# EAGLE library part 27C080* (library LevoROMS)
27C080 High Performance CMOS EPROM

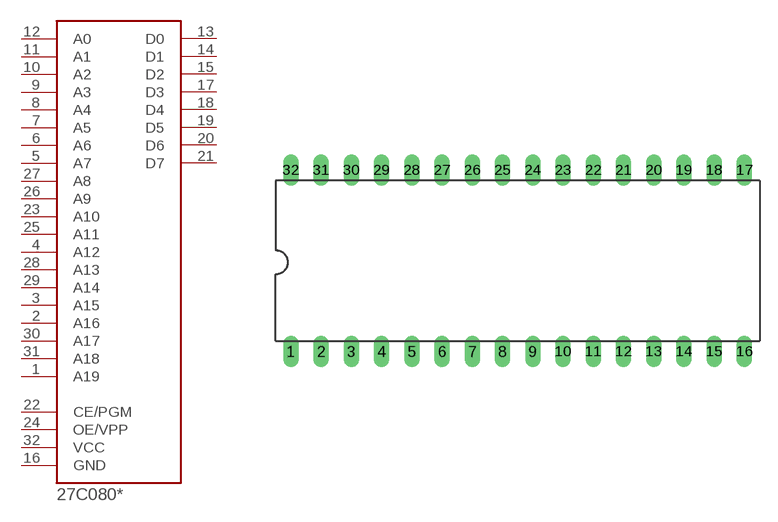
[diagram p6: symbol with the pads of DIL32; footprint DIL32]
Designator prefix IC

## 27C080  [DIL32]
1  A19  in
2  A16  in
3  A15  in
4  A12  in
5  A7  in
6  A6  in
7  A5  in
8  A4  in
9  A3  in
10  A2  in
11  A1  in
12  A0  in
13  D0
14  D1
15  D2
16  GND  pwr
17  D3
18  D4
19  D5
20  D6
21  D7
22  CE/PGM
23  A10  in
24  OE/VPP
25  A11  in
26  A9  in
27  A8  in
28  A13  in
29  A14  in
30  A17  in
31  A18  in
32  VCC  pwr

## Footprint DIL32 (pad centres in mm)
Dual In Line Package
drill 0.813 long: 1 -24.13,-7.62; 2 -21.59,-7.62; 3 -19.05,-7.62; 4 -16.51,-7.62; 5 -13.97,-7.62; 6 -11.43,-7.62; 7 -8.89,-7.62; 8 -6.35,-7.62; 9 -3.81,-7.62; 10 -1.27,-7.62; 11 1.27,-7.62; 12 3.81,-7.62; 13 6.35,-7.62; 14 8.89,-7.62; 15 11.43,-7.62; 16 13.97,-7.62; 17 13.97,7.62; 18 11.43,7.62; 19 8.89,7.62; 20 6.35,7.62; 21 3.81,7.62; 22 1.27,7.62; 23 -1.27,7.62; 24 -3.81,7.62; 25 -6.35,7.62; 26 -8.89,7.62; 27 -11.43,7.62; 28 -13.97,7.62; 29 -16.51,7.62; 30 -19.05,7.62; 31 -21.59,7.62; 32 -24.13,7.62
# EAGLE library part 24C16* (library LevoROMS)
16K (2048 x 8) 2-wire Serial EEPROM

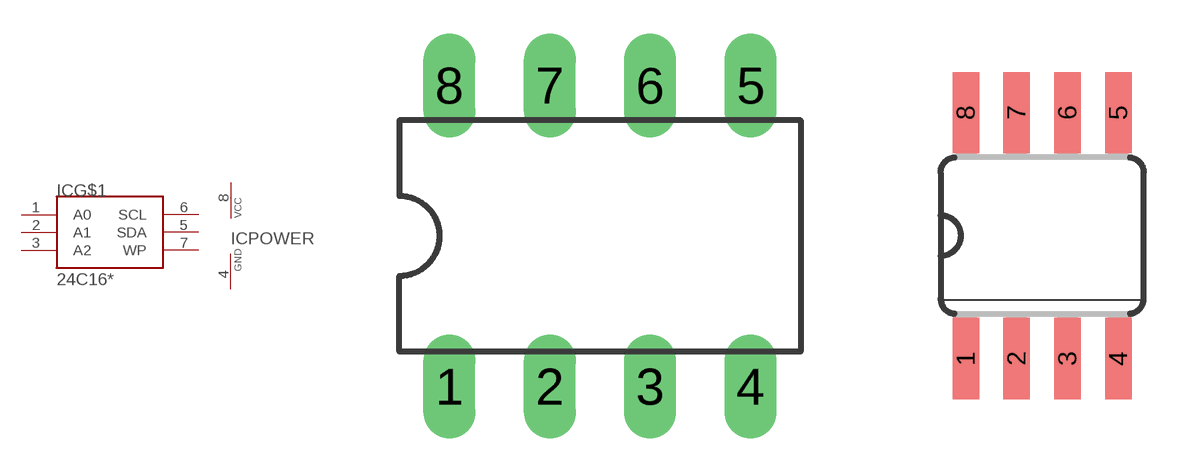
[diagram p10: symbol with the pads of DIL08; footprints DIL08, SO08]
Designator prefix IC; gates G$1=24C02 POWER=VCC-GND

## 24C16DIL  [DIL08]
1  G$1:A0  in
2  G$1:A1  in
3  G$1:A2  in
4  POWER:GND  pwr
5  G$1:SDA
6  G$1:SCL
7  G$1:WP
8  POWER:VCC  pwr

## 24C16SOIC  [SO08]
Pads as for DIL08

## Footprint DIL08 (pad centres in mm)
Dual In Line Package
drill 0.813 long: 1 -3.81,-3.81; 2 -1.27,-3.81; 3 1.27,-3.81; 4 3.81,-3.81; 5 3.81,3.81; 6 1.27,3.81; 7 -1.27,3.81; 8 -3.81,3.81

## Footprint SO08 (pad centres in mm)
Small Outline package 150 mil
smd 0.66 x 2.032: 1 -1.905,-3.073; 2 -0.635,-3.073; 3 0.635,-3.073; 4 1.905,-3.073; 5 1.905,3.073; 6 0.635,3.073; 7 -0.635,3.073; 8 -1.905,3.073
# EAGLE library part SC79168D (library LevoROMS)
Motorola SC79168D Labai slapta mikroschema Printerio HP 400 serijos desifratorius su raktais

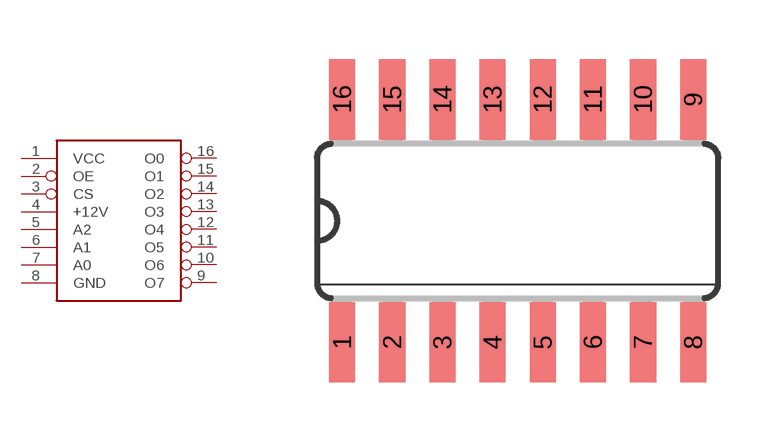
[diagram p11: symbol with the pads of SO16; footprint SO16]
Designator prefix IC

## SC79168D  [SO16]
1  VCC  pwr
2  OE  in
3  CS  in
4  +12V  pwr
5  A2  in
6  A1  in
7  A0  in
8  GND  pwr
9  O7  hiz
10  O6  hiz
11  O5  hiz
12  O4  hiz
13  O3  hiz
14  O2  hiz
15  O1  hiz
16  O0  hiz

## Footprint SO16 (pad centres in mm)
Small Outline package 150 mil
smd 0.66 x 2.032: 1 -4.445,-3.073; 2 -3.175,-3.073; 3 -1.905,-3.073; 4 -0.635,-3.073; 5 0.635,-3.073; 6 1.905,-3.073; 7 3.175,-3.073; 8 4.445,-3.073; 9 4.445,3.073; 10 3.175,3.073; 11 1.905,3.073; 12 0.635,3.073; 13 -0.635,3.073; 14 -1.905,3.073; 15 -3.175,3.073; 16 -4.445,3.073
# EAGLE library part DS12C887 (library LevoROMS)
DS12C887 Real Time Clock RTC

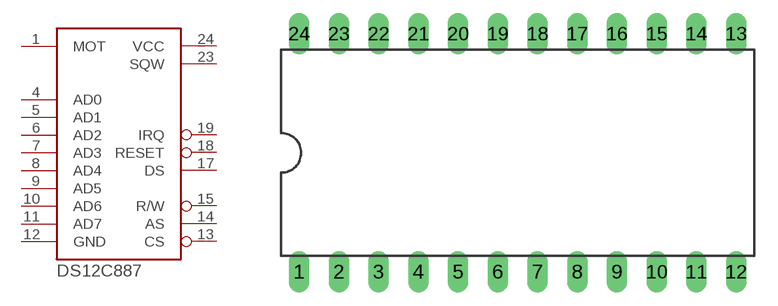
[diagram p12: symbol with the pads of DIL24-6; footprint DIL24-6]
Designator prefix IC

## DS12C887  [DIL24-6]
1  MOT
4  AD0
5  AD1
6  AD2
7  AD3
8  AD4
9  AD5
10  AD6
11  AD7
12  GND  pwr
13  CS
14  AS
15  R/W
17  DS  in
18  RESET
19  IRQ
23  SQW  out
24  VCC  pwr

## Footprint DIL24-6 (pad centres in mm)
Dual In Line Package 0.6 inch
drill 0.813 long: 1 -13.97,-7.62; 2 -11.43,-7.62; 3 -8.89,-7.62; 4 -6.35,-7.62; 5 -3.81,-7.62; 6 -1.27,-7.62; 7 1.27,-7.62; 8 3.81,-7.62; 9 6.35,-7.62; 10 8.89,-7.62; 11 11.43,-7.62; 12 13.97,-7.62; 13 13.97,7.62; 14 11.43,7.62; 15 8.89,7.62; 16 6.35,7.62; 17 3.81,7.62; 18 1.27,7.62; 19 -1.27,7.62; 20 -3.81,7.62; 21 -6.35,7.62; 22 -8.89,7.62; 23 -11.43,7.62; 24 -13.97,7.62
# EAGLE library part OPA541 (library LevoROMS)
OPA541 High Power Monolithic OPERATIONAL AMPLIFIER The OPA541 is a power operational amplifier capable of operation from power supplies up to ±40V and delivering continuous output currents up to 5A. Internal current limit circuitry can be user-programmed with a single external resistor, protecting the amplifier and load from fault conditions The OPA541 is available in an 11-pin power plastic package and an industry-standard 8-pin TO-3 hermetic package. The power plastic package has a copper- lead frame to maximize heat transfer. The TO-3 package is isolated from all circuitry, allowing it to be mounted directly to a heat sink without special insulators. BurrBrown/TI product

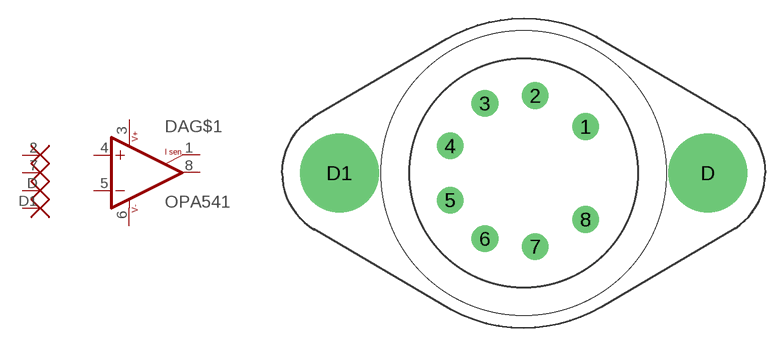
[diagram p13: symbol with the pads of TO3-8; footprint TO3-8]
Designator prefix DA; gates G$1=OPA541 G$2=NC G$3=NC G$4=NC G$5=NC

## OPA541BM  [TO3-8]
1  G$1:CURRENT-SENSE  pas
2  G$2:NC  nc
3  G$1:V+  pwr
4  G$1:+IN  in
5  G$1:-IN  in
6  G$1:V-  pwr
7  G$3:NC  nc
8  G$1:OUT  out
D  G$4:NC  nc
D1  G$5:NC  nc

## Footprint TO3-8 (pad centres in mm)
TO3-8 Metal can package. Perdaryta is paprasto tranzo.
drill 0.813 pad 2.184 round: 1 1.27,3.81; 2 -2.857,6.35; 3 -6.985,5.715; 4 -9.842,2.223; 5 -9.842,-2.223; 6 -6.985,-5.397; 7 -2.857,-6.032; 8 1.27,-3.81
drill 4.115 pad 6.477 round: D 11.303,0; D1 -18.923,0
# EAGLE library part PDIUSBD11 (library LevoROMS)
USB device with serial interface The Universal Serial Bus hub PDIUSBD11 is a cost and feature-optimized USB interface device. It is used in microcontroller-based systems and communicates with the system microcontroller over the high speed I2C serial bus... Philips kuryba.

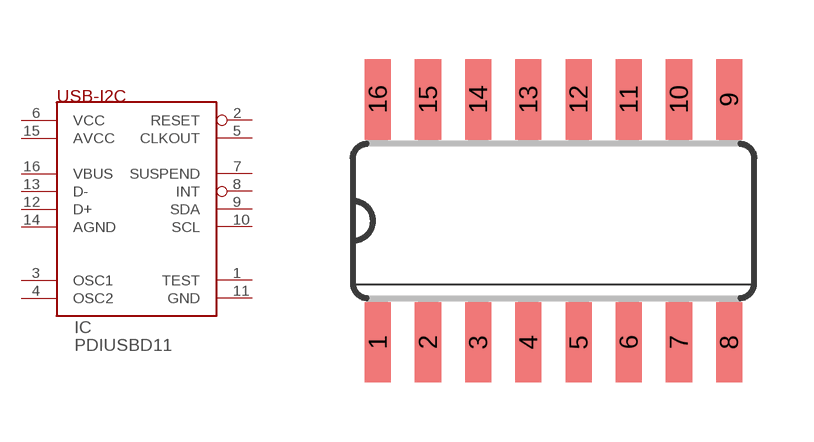
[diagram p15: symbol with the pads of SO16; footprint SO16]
Designator prefix IC

## PDIUSBD11  [SO16]
1  TEST
2  RESET
3  OSC1
4  OSC2
5  CLKOUT  out
6  VCC  pwr
7  SUSPEND
8  INT
9  SDA
10  SCL
11  GND  pwr
12  D+
13  D-
14  AGND  pwr
15  AVCC  pwr
16  VBUS

## Footprint SO16 (pad centres in mm)
Small Outline package 150 mil
smd 0.66 x 2.032: 1 -4.445,-3.073; 2 -3.175,-3.073; 3 -1.905,-3.073; 4 -0.635,-3.073; 5 0.635,-3.073; 6 1.905,-3.073; 7 3.175,-3.073; 8 4.445,-3.073; 9 4.445,3.073; 10 3.175,3.073; 11 1.905,3.073; 12 0.635,3.073; 13 -0.635,3.073; 14 -1.905,3.073; 15 -3.175,3.073; 16 -4.445,3.073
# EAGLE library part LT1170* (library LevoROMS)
LT1170, LT1171, LT1172 100kHz, 5A, 2.5A and 1.25A High Efficiency Switching Regulator. Wide Input Voltage Range: 3V to 60V. Low Quiescent Current: 6mA. Internal 5A Switch (2.5A for LT1171, 1.25A for LT1172). Shutdown Mode Draws Only 50mA Supply Current. Very Few External Parts Required. Self-Protected Against Overloads. Operates in Nearly All Switching Topologies. Flyback-Regulated Mode Has Fully Floating Outputs. Comes in Standard 5-Pin Packages. LT1172 Available in 8-Pin MiniDIP and Surface Mount Packages. Can Be Externally Synchronized

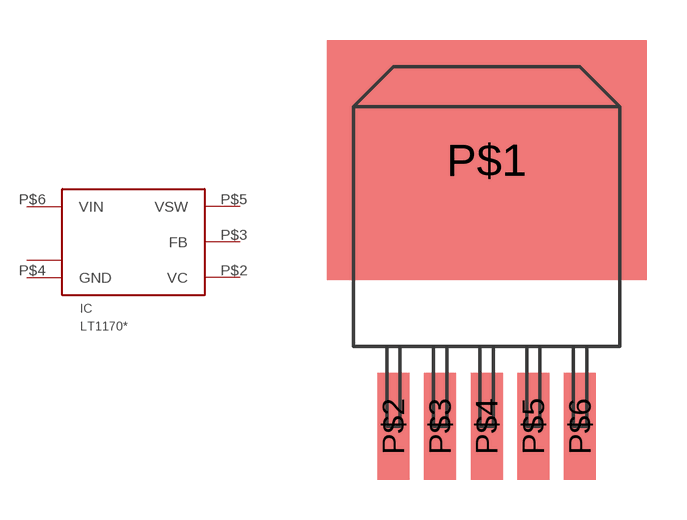
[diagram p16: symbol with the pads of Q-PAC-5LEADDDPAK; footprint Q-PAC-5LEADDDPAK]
Designator prefix IC

## LT1170  [Q-PAC-5LEADDDPAK]
P$1  GNDTAB  pwr
P$2  VC
P$3  FB  in
P$4  GND  pwr
P$5  VSW  pwr
P$6  VIN  pwr

## Footprint Q-PAC-5LEADDDPAK (pad centres in mm)
Q Package, 5 Lead Plastic DD Pak
smd 12 x 9: P$1 0,2
smd 1.2 x 4: P$2 -3.5,-8; P$3 -1.75,-8; P$4 0,-8; P$5 1.75,-8; P$6 3.5,-8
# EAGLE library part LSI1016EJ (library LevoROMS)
LATTICE PROGRAMMABLE DEVICE

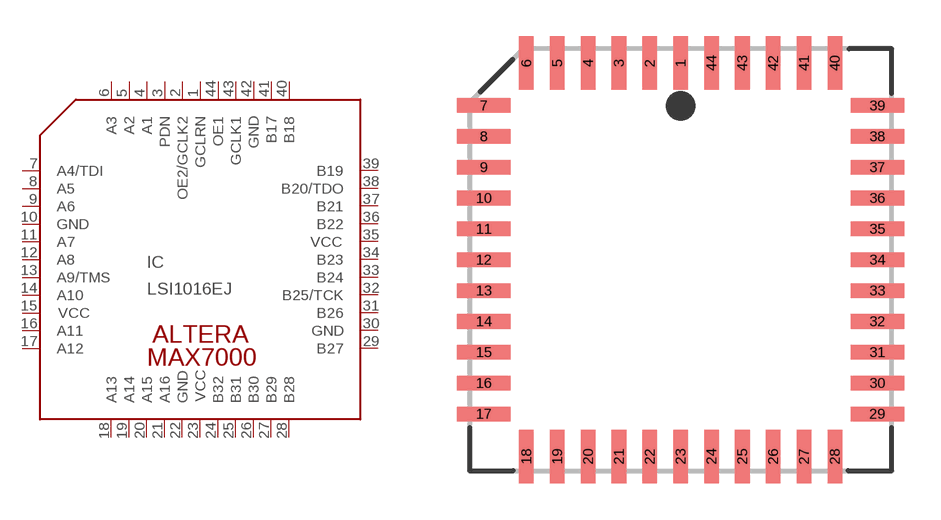
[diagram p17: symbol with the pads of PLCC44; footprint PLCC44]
Designator prefix IC

## LSI1016EJ  [PLCC44]
1  GCLRN  in
2  OE2/GCLK2  in
3  PDN
4  A1
5  A2
6  A3
7  A4/TDI
8  A5
9  A6
10  GND  pwr
11  A7
12  A8
13  A9/TMS
14  A10
15  VCC  pwr
16  A11
17  A12
18  A13
19  A14
20  A15
21  A16
22  GND  pwr
23  VCC  pwr
24  B32
25  B31
26  B30
27  B29
28  B28
29  B27
30  GND  pwr
31  B26
32  B25/TCK
33  B24
34  B23
35  VCC  pwr
36  B22
37  B21
38  B20/TDO
39  B19
40  B18
41  B17
42  GND  pwr
43  GCLK1  in
44  OE1  in

## Footprint PLCC44 (pad centres in mm)
Plastic Leaded Chip Carrier
smd 0.6 x 2.2: 1 0,8.1; 2 -1.27,8.1; 3 -2.54,8.1; 4 -3.81,8.1; 5 -5.08,8.1; 6 -6.35,8.1; 18 -6.35,-8.1; 19 -5.08,-8.1; 20 -3.81,-8.1; 21 -2.54,-8.1; 22 -1.27,-8.1; 23 0,-8.1; 24 1.27,-8.1; 25 2.54,-8.1; 26 3.81,-8.1; 27 5.08,-8.1; 28 6.35,-8.1; 40 6.35,8.1; 41 5.08,8.1; 42 3.81,8.1; 43 2.54,8.1; 44 1.27,8.1
smd 2.2 x 0.6: 7 -8.1,6.35; 8 -8.1,5.08; 9 -8.1,3.81; 10 -8.1,2.54; 11 -8.1,1.27; 12 -8.1,0; 13 -8.1,-1.27; 14 -8.1,-2.54; 15 -8.1,-3.81; 16 -8.1,-5.08; 17 -8.1,-6.35; 29 8.1,-6.35; 30 8.1,-5.08; 31 8.1,-3.81; 32 8.1,-2.54; 33 8.1,-1.27; 34 8.1,0; 35 8.1,1.27; 36 8.1,2.54; 37 8.1,3.81; 38 8.1,5.08; 39 8.1,6.35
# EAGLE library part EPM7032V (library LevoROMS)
ALTERA FLEX MAX7000 EPM7032

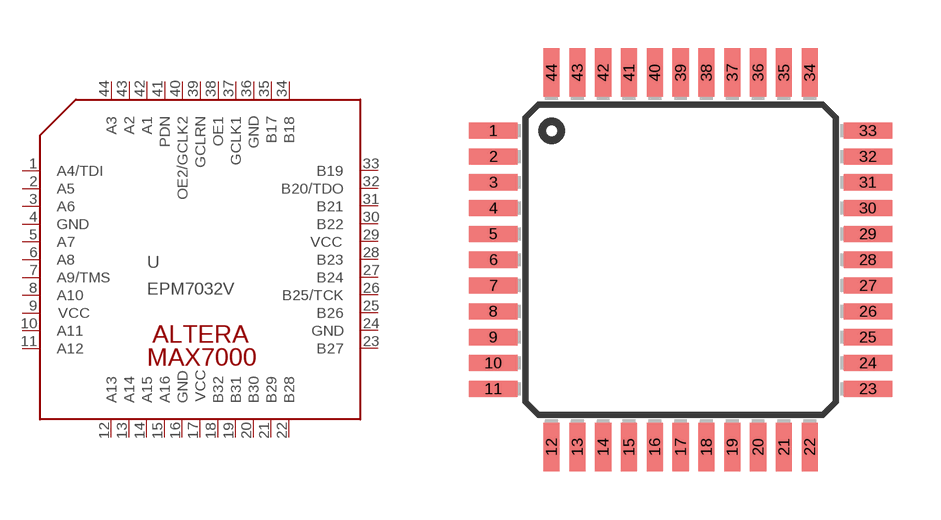
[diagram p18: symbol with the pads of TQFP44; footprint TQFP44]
Designator prefix -

## EPM7032V  [TQFP44]
1  A4/TDI
2  A5
3  A6
4  GND  pwr
5  A7
6  A8
7  A9/TMS
8  A10
9  VCC  pwr
10  A11
11  A12
12  A13
13  A14
14  A15
15  A16
16  GND  pwr
17  VCC  pwr
18  B32
19  B31
20  B30
21  B29
22  B28
23  B27
24  GND  pwr
25  B26
26  B25/TCK
27  B24
28  B23
29  VCC  pwr
30  B22
31  B21
32  B20/TDO
33  B19
34  B18
35  B17
36  GND  pwr
37  GCLK1  in
38  OE1  in
39  GCLRN  in
40  OE2/GCLK2  in
41  PDN
42  A1
43  A2
44  A3

## Footprint TQFP44 (pad centres in mm)
Thin Quad Flat Package
smd 1.5 x 0.5: 1 -5.8,4; 2 -5.8,3.2; 3 -5.8,2.4; 4 -5.8,1.6; 5 -5.8,0.8; 6 -5.8,0; 7 -5.8,-0.8; 8 -5.8,-1.6; 9 -5.8,-2.4; 10 -5.8,-3.2; 11 -5.8,-4; 23 5.8,-4; 24 5.8,-3.2; 25 5.8,-2.4; 26 5.8,-1.6; 27 5.8,-0.8; 28 5.8,0; 29 5.8,0.8; 30 5.8,1.6; 31 5.8,2.4; 32 5.8,3.2; 33 5.8,4
smd 0.5 x 1.5: 12 -4,-5.8; 13 -3.2,-5.8; 14 -2.4,-5.8; 15 -1.6,-5.8; 16 -0.8,-5.8; 17 0,-5.8; 18 0.8,-5.8; 19 1.6,-5.8; 20 2.4,-5.8; 21 3.2,-5.8; 22 4,-5.8; 34 4,5.8; 35 3.2,5.8; 36 2.4,5.8; 37 1.6,5.8; 38 0.8,5.8; 39 0,5.8; 40 -0.8,5.8; 41 -1.6,5.8; 42 -2.4,5.8; 43 -3.2,5.8; 44 -4,5.8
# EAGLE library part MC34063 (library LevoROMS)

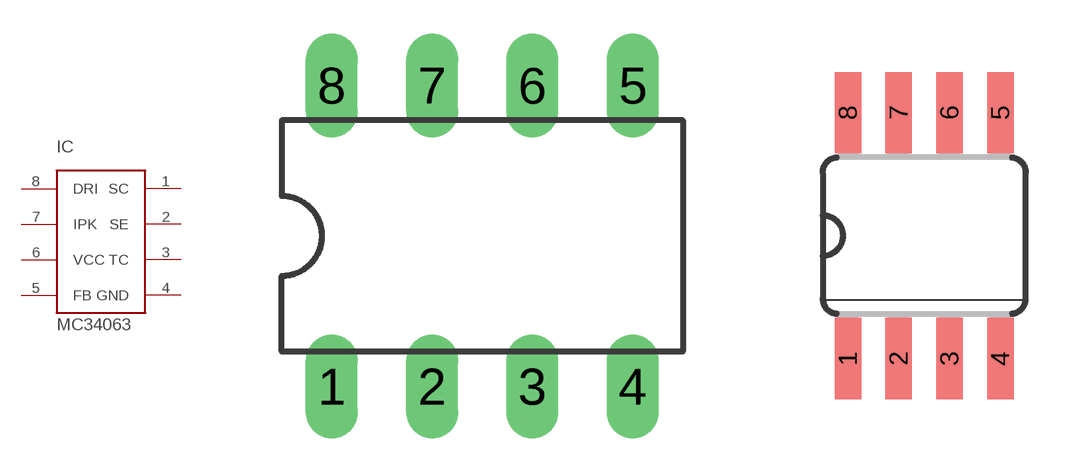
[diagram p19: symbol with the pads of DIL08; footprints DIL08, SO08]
Designator prefix IC

## MC34063N  [DIL08]
1  SC
2  SE
3  TC
4  GND  pwr
5  FB
6  VCC  pwr
7  IPK
8  DRI

## MC34063S  [SO08]
Pads as for DIL08

## Footprint DIL08 (pad centres in mm)
Dual In Line Package
drill 0.813 long: 1 -3.81,-3.81; 2 -1.27,-3.81; 3 1.27,-3.81; 4 3.81,-3.81; 5 3.81,3.81; 6 1.27,3.81; 7 -1.27,3.81; 8 -3.81,3.81

## Footprint SO08 (pad centres in mm)
Small Outline package 150 mil
smd 0.66 x 2.032: 1 -1.905,-3.073; 2 -0.635,-3.073; 3 0.635,-3.073; 4 1.905,-3.073; 5 1.905,3.073; 6 0.635,3.073; 7 -0.635,3.073; 8 -1.905,3.073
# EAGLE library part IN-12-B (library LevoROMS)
IN-12-B (su tasku)

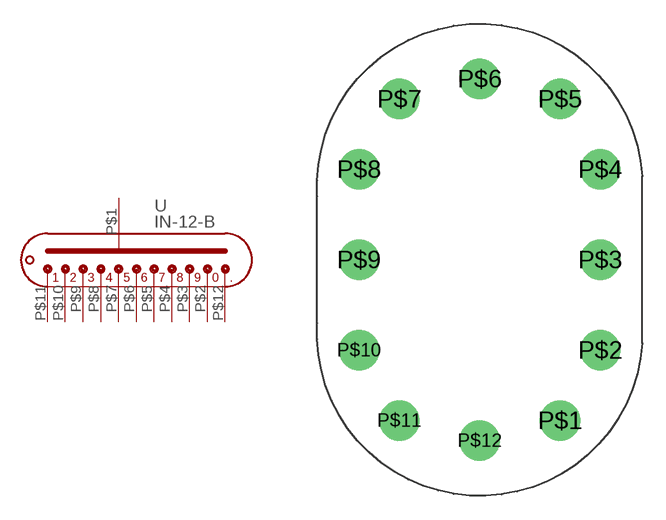
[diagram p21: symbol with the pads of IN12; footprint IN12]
Designator prefix -

## IN-12-B  [IN12]
P$1  A1  pas
P$2  0  pas
P$3  9  pas
P$4  8  pas
P$5  7  pas
P$6  6  pas
P$7  5  pas
P$8  4  pas
P$9  3  pas
P$10  2  pas
P$11  1  pas
P$12  10  pas

## Footprint IN12 (pad centres in mm)
IN-12 tipo Nixie.
drill 1 pad 2.54 round: P$1 5.08,-10.16; P$2 7.62,-5.715; P$3 7.62,0; P$4 7.62,5.715; P$5 5.08,10.16; P$6 0,11.43; P$7 -5.08,10.16; P$8 -7.62,5.715; P$9 -7.62,0; P$10 -7.62,-5.715; P$11 -5.08,-10.16; P$12 0,-11.43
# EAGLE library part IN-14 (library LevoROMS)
IN-14. Lituojamas. Taip pat IN-19

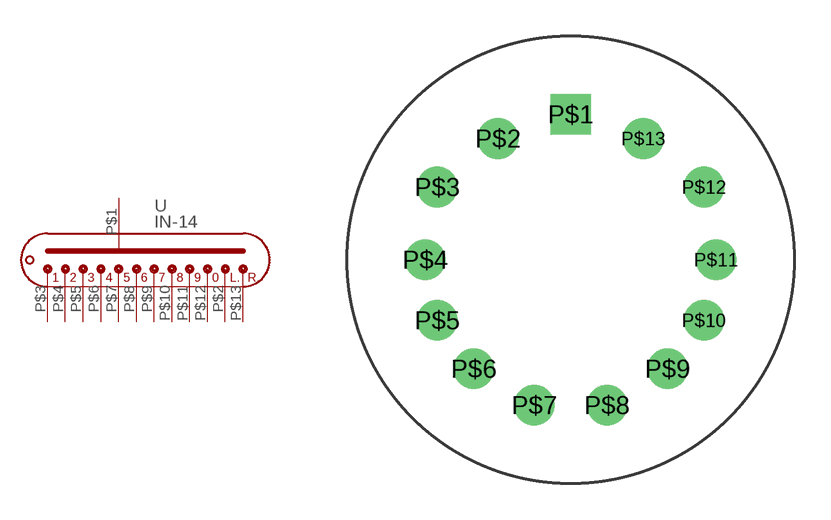
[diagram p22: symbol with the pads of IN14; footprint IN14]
Designator prefix -

## IN-14  [IN14]
P$1  A1  pas
P$2  10  pas
P$3  1  pas
P$4  2  pas
P$5  3  pas
P$6  4  pas
P$7  5  pas
P$8  6  pas
P$9  7  pas
P$10  8  pas
P$11  9  pas
P$12  0  pas
P$13  11  pas

## Footprint IN14 (pad centres in mm)
IN-14 (smulkus variantas)
drill 0.6 pad 1.676 square: P$1 0,6
drill 0.6 pad 1.676 round: P$2 -3,5; P$3 -5.5,3; P$4 -6,0; P$5 -5.5,-2.5; P$6 -4,-4.5; P$7 -1.5,-6; P$8 1.5,-6; P$9 4,-4.5; P$10 5.5,-2.5; P$11 6,0; P$12 5.5,3; P$13 3,5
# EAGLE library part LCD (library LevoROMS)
Standartinis LCD modulis

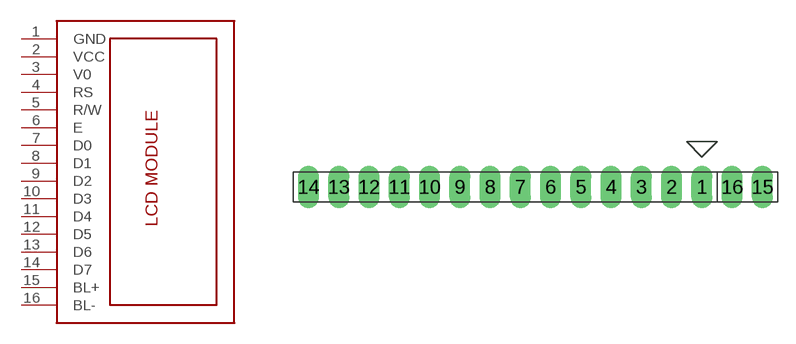
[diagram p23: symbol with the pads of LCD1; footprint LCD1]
Designator prefix LCD

## LCD  [LCD1]
1  GND  pwr
2  VCC  pwr
3  V0
4  RS  in
5  R/W  in
6  E
7  D0
8  D1
9  D2
10  D3
11  D4
12  D5
13  D6
14  D7
15  BL+  pwr
16  BL-  pwr

## Footprint LCD1 (pad centres in mm)
LCD modulis su pasvietimu
drill 0.6 pad 1.778 long: 1 12.7,-1.27; 2 10.16,-1.27; 3 7.62,-1.27; 4 5.08,-1.27; 5 2.54,-1.27; 6 0,-1.27; 7 -2.54,-1.27; 8 -5.08,-1.27; 9 -7.62,-1.27; 10 -10.16,-1.27; 11 -12.7,-1.27; 12 -15.24,-1.27; 13 -17.78,-1.27; 14 -20.32,-1.27; 15 17.78,-1.27; 16 15.24,-1.27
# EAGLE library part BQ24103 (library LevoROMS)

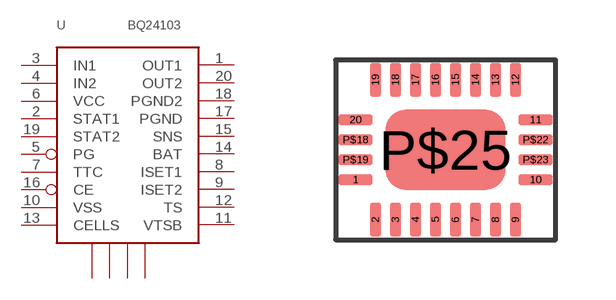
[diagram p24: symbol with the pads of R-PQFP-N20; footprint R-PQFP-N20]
Designator prefix -

## BQ24103  [R-PQFP-N20]
1  OUT1  pwr
2  STAT1  out
3  IN1  pwr
4  IN2  pwr
5  PG  out
6  VCC  pwr
7  TTC
8  ISET1  in
9  ISET2  in
10  VSS  pwr
11  VTSB  in
12  TS  in
13  CELLS  in
14  BAT  in
15  SNS  in
16  CE  in
17  PGND  pwr
18  PGND2  pwr
19  STAT2  out
20  OUT2  pwr
P$18  PAD1  nc
P$19  PAD2  nc
P$22  PAD3  nc
P$23  PAD4  nc

## Footprint R-PQFP-N20 (pad centres in mm)
smd 0.85 x 0.28: 1 -3.5,0; 10 1,0; 11 1,1.5; 20 -3.5,1.5; P$18 -3.5,1; P$19 -3.5,0.5; P$22 1,1; P$23 1,0.5
smd 0.28 x 0.85: 2 -3,-1; 3 -2.5,-1; 4 -2,-1; 5 -1.5,-1; 6 -1,-1; 7 -0.5,-1; 8 0,-1; 9 0.5,-1; 12 0.5,2.5; 13 0,2.5; 14 -0.5,2.5; 15 -1,2.5; 16 -1.5,2.5; 17 -2,2.5; 18 -2.5,2.5; 19 -3,2.5
smd 3 x 2: P$25 -1.25,0.75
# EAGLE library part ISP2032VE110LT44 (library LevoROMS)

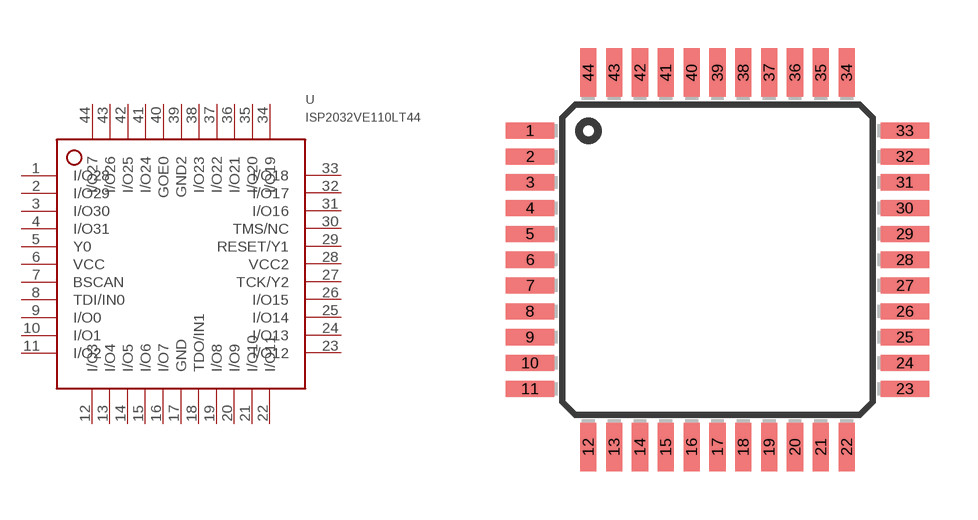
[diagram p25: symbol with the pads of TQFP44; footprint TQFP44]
Designator prefix U

## ISP2032VE110LT44  [TQFP44]
1  I/O28
2  I/O29
3  I/O30
4  I/O31
5  Y0
6  VCC  pwr
7  BSCAN
8  TDI/IN0
9  I/O0
10  I/O1
11  I/O2
12  I/O3
13  I/O4
14  I/O5
15  I/O6
16  I/O7
17  GND  pwr
18  TDO/IN1
19  I/O8
20  I/O9
21  I/O10
22  I/O11
23  I/O12
24  I/O13
25  I/O14
26  I/O15
27  TCK/Y2
28  VCC2  pwr
29  RESET/Y1
30  TMS/NC
31  I/O16
32  I/O17
33  I/O18
34  I/O19
35  I/O20
36  I/O21
37  I/O22
38  I/O23
39  GND2  pwr
40  GOE0
41  I/O24
42  I/O25
43  I/O26
44  I/O27

## Footprint TQFP44 (pad centres in mm)
Thin Quad Flat Package
smd 1.5 x 0.5: 1 -5.8,4; 2 -5.8,3.2; 3 -5.8,2.4; 4 -5.8,1.6; 5 -5.8,0.8; 6 -5.8,0; 7 -5.8,-0.8; 8 -5.8,-1.6; 9 -5.8,-2.4; 10 -5.8,-3.2; 11 -5.8,-4; 23 5.8,-4; 24 5.8,-3.2; 25 5.8,-2.4; 26 5.8,-1.6; 27 5.8,-0.8; 28 5.8,0; 29 5.8,0.8; 30 5.8,1.6; 31 5.8,2.4; 32 5.8,3.2; 33 5.8,4
smd 0.5 x 1.5: 12 -4,-5.8; 13 -3.2,-5.8; 14 -2.4,-5.8; 15 -1.6,-5.8; 16 -0.8,-5.8; 17 0,-5.8; 18 0.8,-5.8; 19 1.6,-5.8; 20 2.4,-5.8; 21 3.2,-5.8; 22 4,-5.8; 34 4,5.8; 35 3.2,5.8; 36 2.4,5.8; 37 1.6,5.8; 38 0.8,5.8; 39 0,5.8; 40 -0.8,5.8; 41 -1.6,5.8; 42 -2.4,5.8; 43 -3.2,5.8; 44 -4,5.8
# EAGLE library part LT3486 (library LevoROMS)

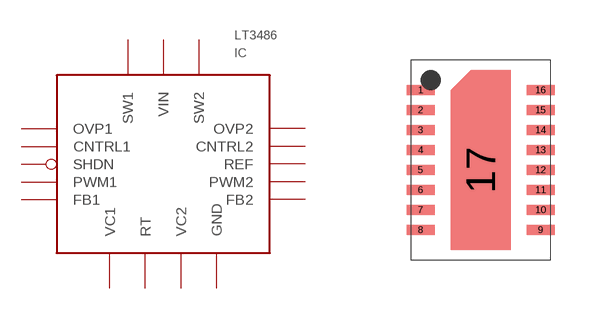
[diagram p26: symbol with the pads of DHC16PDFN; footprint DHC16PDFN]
Designator prefix IC

## LT3486  [DHC16PDFN]
1  SW1  out
2  VIN  pwr
3  OVP1  in
4  RT
5  VC1
6  FB1  in
7  CNTRL1  in
8  PWM1  in
9  PWM2
10  CNTRL2  in
11  FB2  in
12  VC2
13  SHDN  in
14  OVP2  in
15  REF  out
16  SW2  out
17  GND  pwr

## Footprint DHC16PDFN (pad centres in mm)
smd 0.7 x 0.25: 1 -1.5,2; 2 -1.5,1.5; 3 -1.5,1; 4 -1.5,0.5; 5 -1.5,0; 6 -1.5,-0.5; 7 -1.5,-1; 8 -1.5,-1.5; 9 1.5,-1.5; 10 1.5,-1; 11 1.5,-0.5; 12 1.5,0; 13 1.5,0.5; 14 1.5,1; 15 1.5,1.5; 16 1.5,2
smd 1.067 x 2.184: 17 0,0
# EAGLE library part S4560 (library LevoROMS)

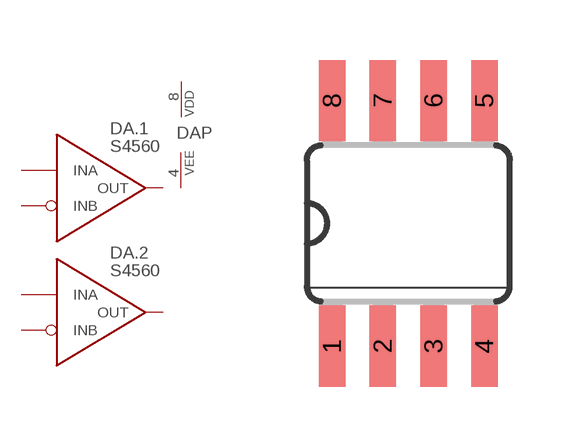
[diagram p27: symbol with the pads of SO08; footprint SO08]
Designator prefix DA; gates .1=S4560 P=POWERFOROPAMP .2=S4560

## S4560  [SO08]
1  .1:OUT  out
2  .1:INB  in
3  .1:INA  in
4  P:VEE  pwr
5  .2:INA  in
6  .2:INB  in
7  .2:OUT  out
8  P:VDD  pwr

## Footprint SO08 (pad centres in mm)
Small Outline package 150 mil
smd 0.66 x 2.032: 1 -1.905,-3.073; 2 -0.635,-3.073; 3 0.635,-3.073; 4 1.905,-3.073; 5 1.905,3.073; 6 0.635,3.073; 7 -0.635,3.073; 8 -1.905,3.073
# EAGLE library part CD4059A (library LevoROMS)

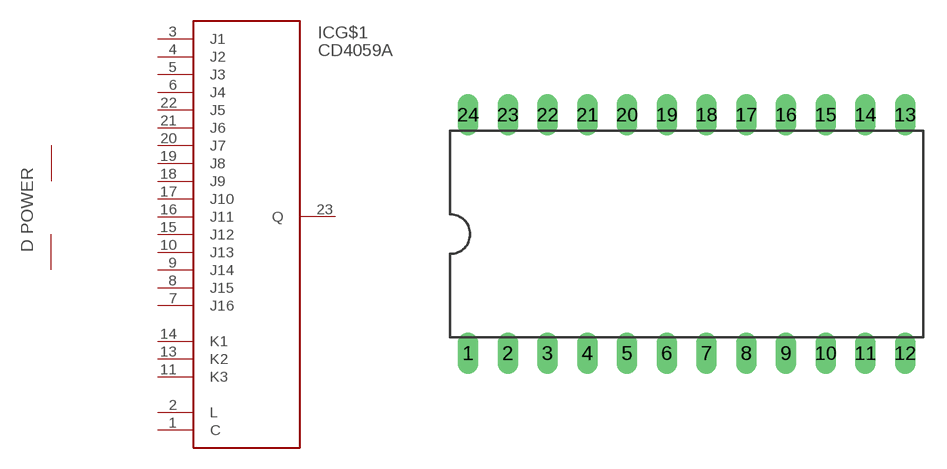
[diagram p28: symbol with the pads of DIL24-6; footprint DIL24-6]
Designator prefix IC; gates G$1=CD4059A G$2=DIG-P

## CD4059A  [DIL24-6]
1  G$1:C  in
2  G$1:L  in
3  G$1:J1  in
4  G$1:J2  in
5  G$1:J3  in
6  G$1:J4  in
7  G$1:J16  in
8  G$1:J15  in
9  G$1:J14  in
10  G$1:J13  in
11  G$1:K3  in
12  G$2:GND  pwr
13  G$1:K2  in
14  G$1:K1  in
15  G$1:J12  in
16  G$1:J11  in
17  G$1:J10  in
18  G$1:J9  in
19  G$1:J8  in
20  G$1:J7  in
21  G$1:J6  in
22  G$1:J5  in
23  G$1:Q  out
24  G$2:VCC  pwr

## Footprint DIL24-6 (pad centres in mm)
Dual In Line Package 0.6 inch
drill 0.813 long: 1 -13.97,-7.62; 2 -11.43,-7.62; 3 -8.89,-7.62; 4 -6.35,-7.62; 5 -3.81,-7.62; 6 -1.27,-7.62; 7 1.27,-7.62; 8 3.81,-7.62; 9 6.35,-7.62; 10 8.89,-7.62; 11 11.43,-7.62; 12 13.97,-7.62; 13 13.97,7.62; 14 11.43,7.62; 15 8.89,7.62; 16 6.35,7.62; 17 3.81,7.62; 18 1.27,7.62; 19 -1.27,7.62; 20 -3.81,7.62; 21 -6.35,7.62; 22 -8.89,7.62; 23 -11.43,7.62; 24 -13.97,7.62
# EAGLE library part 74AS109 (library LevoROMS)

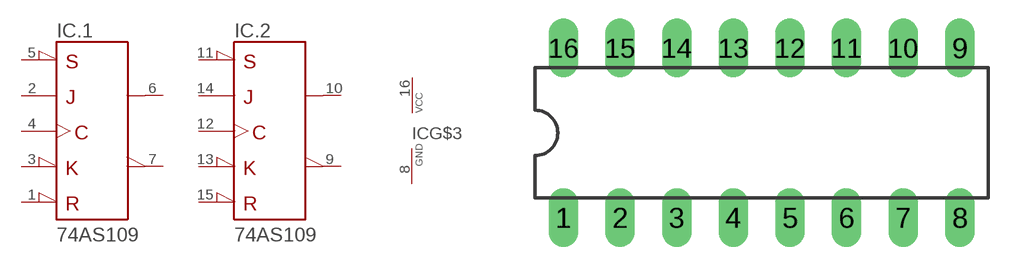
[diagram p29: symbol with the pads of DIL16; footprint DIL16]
Designator prefix IC; gates .1=74AS109 .2=74AS109 G$3=VCC-GND

## 74AS109  [DIL16]
1  .1:CLR\  in
2  .1:J  in
3  .1:K\  in
4  .1:CLK  in
5  .1:PRE\  in
6  .1:Q  out
7  .1:Q\  out
8  G$3:GND  pwr
9  .2:Q\  out
10  .2:Q  out
11  .2:PRE\  in
12  .2:CLK  in
13  .2:K\  in
14  .2:J  in
15  .2:CLR\  in
16  G$3:VCC  pwr

## Footprint DIL16 (pad centres in mm)
Dual In Line Package
drill 0.813 long: 1 -8.89,-3.81; 2 -6.35,-3.81; 3 -3.81,-3.81; 4 -1.27,-3.81; 5 1.27,-3.81; 6 3.81,-3.81; 7 6.35,-3.81; 8 8.89,-3.81; 9 8.89,3.81; 10 6.35,3.81; 11 3.81,3.81; 12 1.27,3.81; 13 -1.27,3.81; 14 -3.81,3.81; 15 -6.35,3.81; 16 -8.89,3.81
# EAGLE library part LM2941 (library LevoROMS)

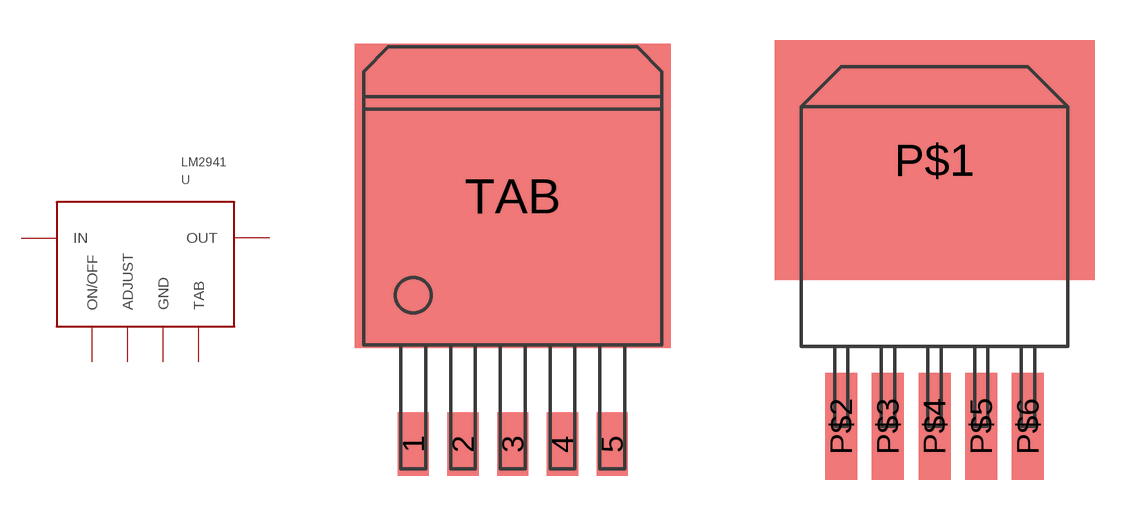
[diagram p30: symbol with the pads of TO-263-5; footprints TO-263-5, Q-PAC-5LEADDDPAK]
Designator prefix U

## LM2941S  [TO-263-5]
1  ADJUST  in
2  ON/OFF  in
3  GND  pwr
4  IN  pwr
5  OUT  pwr
TAB  TAB  pwr

## LM2941D  [Q-PAC-5LEADDDPAK]
P$1  TAB  pwr
P$2  ADJUST  in
P$3  ON/OFF  in
P$4  GND  pwr
P$5  IN  pwr
P$6  OUT  pwr

## Footprint TO-263-5 (pad centres in mm)
smd 1.07 x 2.16: 1 -3.4,-8.5; 2 -1.7,-8.5; 3 0,-8.5; 4 1.7,-8.5; 5 3.4,-8.5
smd 10.8 x 10.41: TAB 0,0

## Footprint Q-PAC-5LEADDDPAK (pad centres in mm)
Q Package, 5 Lead Plastic DD Pak
smd 12 x 9: P$1 0,2
smd 1.2 x 4: P$2 -3.5,-8; P$3 -1.75,-8; P$4 0,-8; P$5 1.75,-8; P$6 3.5,-8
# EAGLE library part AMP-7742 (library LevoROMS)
Terminal block PCB, mount straight size wire entry, stackable, 3.5mm pitch

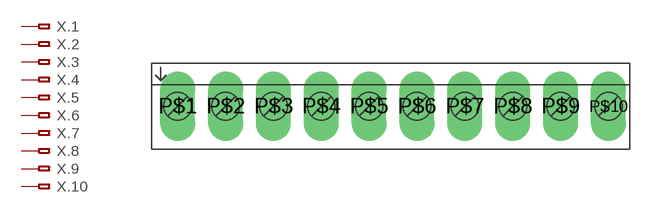
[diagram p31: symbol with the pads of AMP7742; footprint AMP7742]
Designator prefix X; gates .1=K1-V .2=K1 .3=K1 .4=K1 .5=K1 .6=K1 .7=K1 .8=K1 .9=K1 .10=K1

## AMP-7742  [AMP7742]
P$1  .1:A1  pas
P$2  .2:A1  pas
P$3  .3:A1  pas
P$4  .4:A1  pas
P$5  .5:A1  pas
P$6  .6:A1  pas
P$7  .7:A1  pas
P$8  .8:A1  pas
P$9  .9:A1  pas
P$10  .10:A1  pas

## Footprint AMP7742 (pad centres in mm)
drill 1.1 pad 2.54 long: P$1 -14,0; P$2 -10.5,0; P$3 -7,0; P$4 -3.5,0; P$5 0,0; P$6 3.5,0; P$7 7,0; P$8 10.5,0; P$9 14,0; P$10 17.5,0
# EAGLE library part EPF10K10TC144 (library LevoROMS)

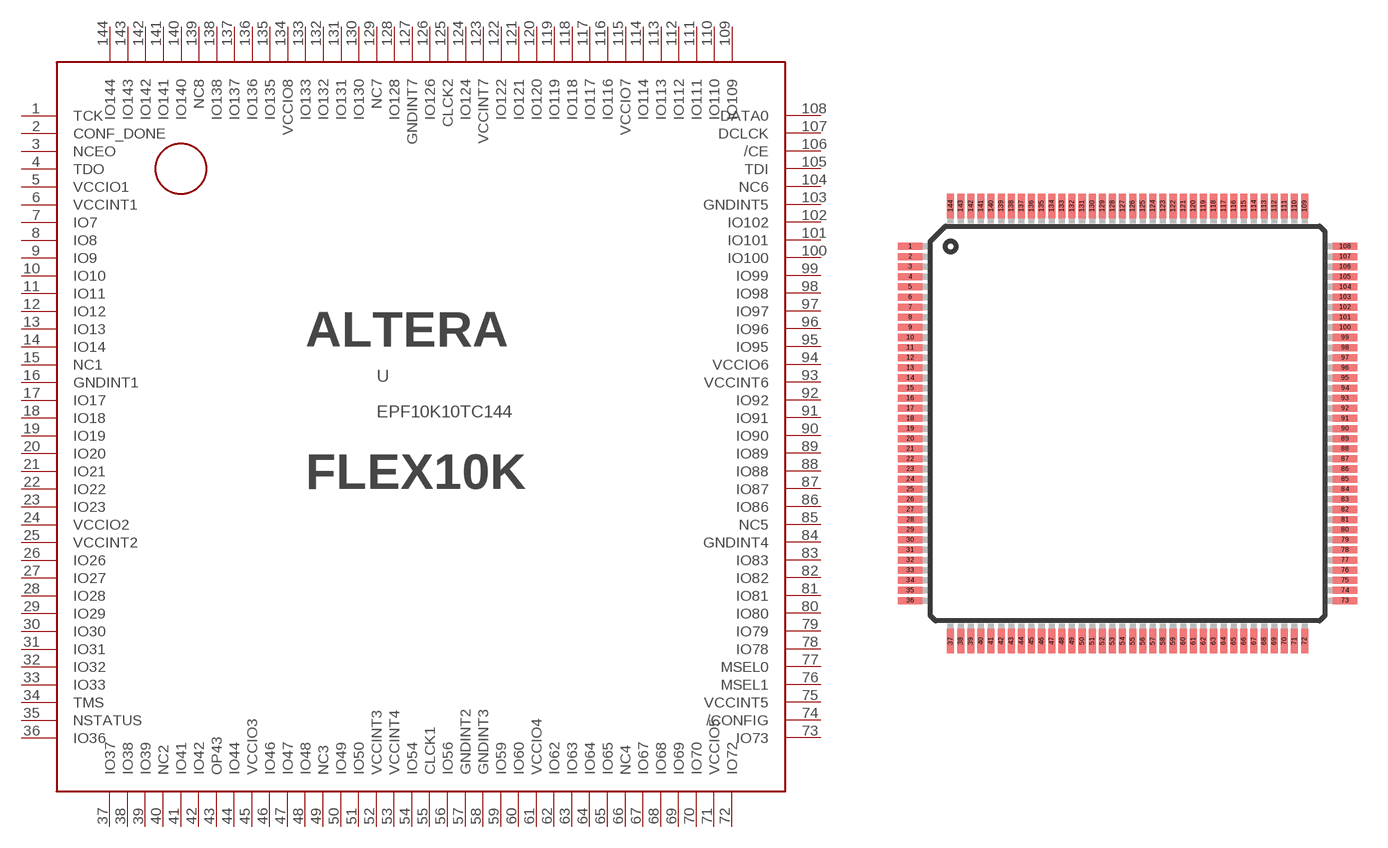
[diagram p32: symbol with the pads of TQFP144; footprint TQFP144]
Designator prefix U

## EPF10K10TC144  [TQFP144]
1  TCK
2  CONF_DONE
3  NCEO
4  TDO
5  VCCIO1
6  VCCINT1
7  IO7
8  IO8
9  IO9
10  IO10
11  IO11
12  IO12
13  IO13
14  IO14
15  NC1
16  GNDINT1
17  IO17
18  IO18
19  IO19
20  IO20
21  IO21
22  IO22
23  IO23
24  VCCIO2
25  VCCINT2
26  IO26
27  IO27
28  IO28
29  IO29
30  IO30
31  IO31
32  IO32
33  IO33
34  TMS
35  NSTATUS
36  IO36
37  IO37
38  IO38
39  IO39
40  NC2
41  IO41
42  IO42
43  OP43
44  IO44
45  VCCIO3
46  IO46
47  IO47
48  IO48
49  NC3
50  IO49
51  IO50
52  VCCINT3
53  VCCINT4
54  IO54
55  CLCK1
56  IO56
57  GNDINT2
58  GNDINT3
59  IO59
60  IO60
61  VCCIO4
62  IO62
63  IO63
64  IO64
65  IO65
66  NC4
67  IO67
68  IO68
69  IO69
70  IO70
71  VCCIO5
72  IO72
73  IO73
74  /CONFIG
75  VCCINT5
76  MSEL1
77  MSEL0
78  IO78
79  IO79
80  IO80
81  IO81
82  IO82
83  IO83
84  GNDINT4
85  NC5
86  IO86
87  IO87
88  IO88
89  IO89
90  IO90
91  IO91
92  IO92
93  VCCINT6
94  VCCIO6
95  IO95
96  IO96
97  IO97
98  IO98
99  IO99
100  IO100
101  IO101
102  IO102
103  GNDINT5
104  NC6
105  TDI
106  /CE
107  DCLCK
108  DATA0
109  IO109
110  IO110
111  IO111
112  IO112
113  IO113
114  IO114
115  VCCIO7
116  IO116
117  IO117
118  IO118
119  IO119
120  IO120
121  IO121
122  IO122
123  VCCINT7
124  IO124
125  CLCK2
126  IO126
127  GNDINT7
128  IO128
129  NC7
130  IO130
131  IO131
132  IO132
133  IO133
134  VCCIO8
135  IO135
136  IO136
137  IO137
138  IO138
139  NC8
140  IO140
141  IO141
142  IO142
143  IO143
144  IO144

## Footprint TQFP144 (pad centres in mm)
smd 1.2 x 0.35: 1 -10.75,8.75; 2 -10.75,8.25; 3 -10.75,7.75; 4 -10.75,7.25; 5 -10.75,6.75; 6 -10.75,6.25; 7 -10.75,5.75; 8 -10.75,5.25; 9 -10.75,4.75; 10 -10.75,4.25; 11 -10.75,3.75; 12 -10.75,3.25; 13 -10.75,2.75; 14 -10.75,2.25; 15 -10.75,1.75; 16 -10.75,1.25; 17 -10.75,0.75; 18 -10.75,0.25; 19 -10.75,-0.25; 20 -10.75,-0.75; 21 -10.75,-1.25; 22 -10.75,-1.75; 23 -10.75,-2.25; 24 -10.75,-2.75; 25 -10.75,-3.25; 26 -10.75,-3.75; 27 -10.75,-4.25; 28 -10.75,-4.75; 29 -10.75,-5.25; 30 -10.75,-5.75; 31 -10.75,-6.25; 32 -10.75,-6.75; 33 -10.75,-7.25; 34 -10.75,-7.75; 35 -10.75,-8.25; 36 -10.75,-8.75; 73 10.75,-8.75; 74 10.75,-8.25; 75 10.75,-7.75; 76 10.75,-7.25; 77 10.75,-6.75; 78 10.75,-6.25; 79 10.75,-5.75; 80 10.75,-5.25; 81 10.75,-4.75; 82 10.75,-4.25; 83 10.75,-3.75; 84 10.75,-3.25; 85 10.75,-2.75; 86 10.75,-2.25; 87 10.75,-1.75; 88 10.75,-1.25; 89 10.75,-0.75; 90 10.75,-0.25; 91 10.75,0.25; 92 10.75,0.75; 93 10.75,1.25; 94 10.75,1.75; 95 10.75,2.25; 96 10.75,2.75; 97 10.75,3.25; 98 10.75,3.75; 99 10.75,4.25; 100 10.75,4.75; 101 10.75,5.25; 102 10.75,5.75; 103 10.75,6.25; 104 10.75,6.75; 105 10.75,7.25; 106 10.75,7.75; 107 10.75,8.25; 108 10.75,8.75
smd 0.35 x 1.2: 37 -8.75,-10.75; 38 -8.25,-10.75; 39 -7.75,-10.75; 40 -7.25,-10.75; 41 -6.75,-10.75; 42 -6.25,-10.75; 43 -5.75,-10.75; 44 -5.25,-10.75; 45 -4.75,-10.75; 46 -4.25,-10.75; 47 -3.75,-10.75; 48 -3.25,-10.75; 49 -2.75,-10.75; 50 -2.25,-10.75; 51 -1.75,-10.75; 52 -1.25,-10.75; 53 -0.75,-10.75; 54 -0.25,-10.75; 55 0.25,-10.75; 56 0.75,-10.75; 57 1.25,-10.75; 58 1.75,-10.75; 59 2.25,-10.75; 60 2.75,-10.75; 61 3.25,-10.75; 62 3.75,-10.75; 63 4.25,-10.75; 64 4.75,-10.75; 65 5.25,-10.75; 66 5.75,-10.75; 67 6.25,-10.75; 68 6.75,-10.75; 69 7.25,-10.75; 70 7.75,-10.75; 71 8.25,-10.75; 72 8.75,-10.75; 109 8.75,10.75; 110 8.25,10.75; 111 7.75,10.75; 112 7.25,10.75; 113 6.75,10.75; 114 6.25,10.75; 115 5.75,10.75; 116 5.25,10.75; 117 4.75,10.75; 118 4.25,10.75; 119 3.75,10.75; 120 3.25,10.75; 121 2.75,10.75; 122 2.25,10.75; 123 1.75,10.75; 124 1.25,10.75; 125 0.75,10.75; 126 0.25,10.75; 127 -0.25,10.75; 128 -0.75,10.75; 129 -1.25,10.75; 130 -1.75,10.75; 131 -2.25,10.75; 132 -2.75,10.75; 133 -3.25,10.75; 134 -3.75,10.75; 135 -4.25,10.75; 136 -4.75,10.75; 137 -5.25,10.75; 138 -5.75,10.75; 139 -6.25,10.75; 140 -6.75,10.75; 141 -7.25,10.75; 142 -7.75,10.75; 143 -8.25,10.75; 144 -8.75,10.75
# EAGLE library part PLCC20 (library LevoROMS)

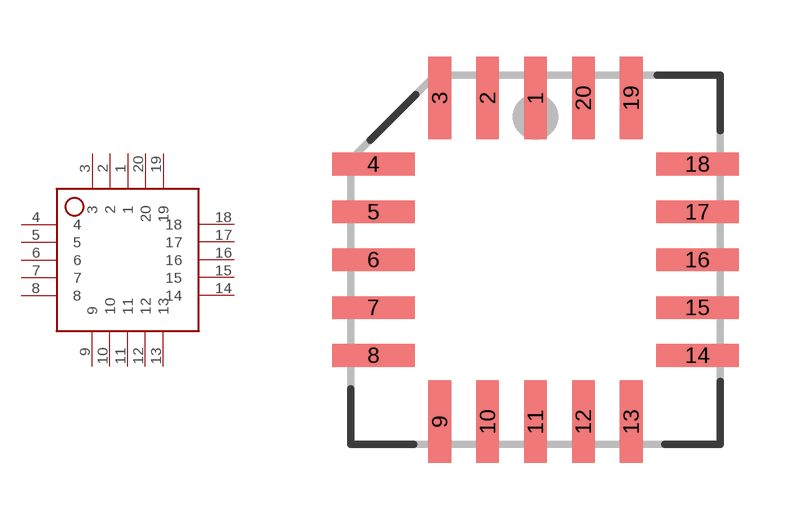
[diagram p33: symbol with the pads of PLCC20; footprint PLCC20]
Designator prefix U

## PLCC20  [PLCC20]
1  1
2  2
3  3
4  4
5  5
6  6
7  7
8  8
9  9
10  10
11  11
12  12
13  13
14  14
15  15
16  16
17  17
18  18
19  19
20  20

## Footprint PLCC20 (pad centres in mm)
Plastic Leaded Chip Carrier IPC standard
smd 0.6 x 2.2: 1 0,4.3; 2 -1.27,4.3; 3 -2.54,4.3; 9 -2.54,-4.3; 10 -1.27,-4.3; 11 0,-4.3; 12 1.27,-4.3; 13 2.54,-4.3; 19 2.54,4.3; 20 1.27,4.3
smd 2.2 x 0.6: 4 -4.3,2.54; 5 -4.3,1.27; 6 -4.3,0; 7 -4.3,-1.27; 8 -4.3,-2.54; 14 4.3,-2.54; 15 4.3,-1.27; 16 4.3,0; 17 4.3,1.27; 18 4.3,2.54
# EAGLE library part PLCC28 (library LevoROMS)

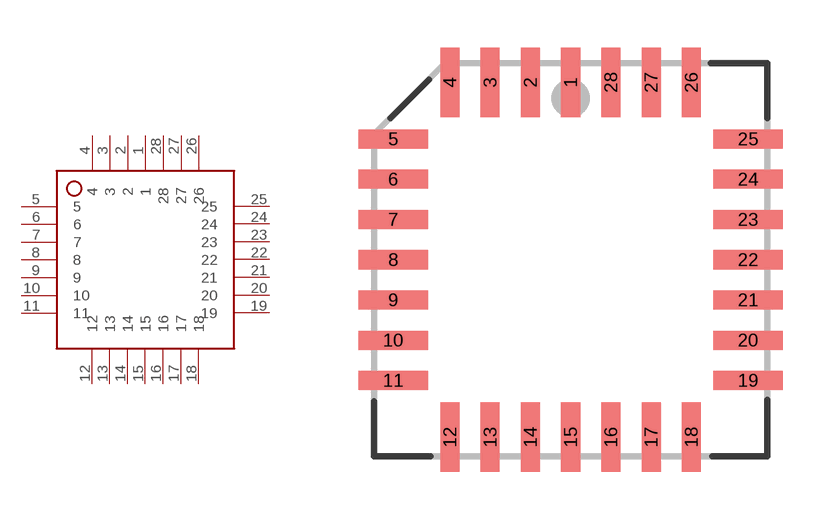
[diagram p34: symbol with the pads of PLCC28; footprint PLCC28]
Designator prefix -

## PLCC28  [PLCC28]
1  1
2  2
3  3
4  4
5  5
6  6
7  7
8  8
9  9
10  10
11  11
12  12
13  13
14  14
15  15
16  16
17  17
18  18
19  19
20  20
21  21
22  22
23  23
24  24
25  25
26  26
27  27
28  28

## Footprint PLCC28 (pad centres in mm)
Plastic Leaded Chip Carrier IPC standard
smd 0.6 x 2.2: 1 0,5.6; 2 -1.27,5.6; 3 -2.54,5.6; 4 -3.81,5.6; 12 -3.81,-5.6; 13 -2.54,-5.6; 14 -1.27,-5.6; 15 0,-5.6; 16 1.27,-5.6; 17 2.54,-5.6; 18 3.81,-5.6; 26 3.81,5.6; 27 2.54,5.6; 28 1.27,5.6
smd 2.2 x 0.6: 5 -5.6,3.81; 6 -5.6,2.54; 7 -5.6,1.27; 8 -5.6,0; 9 -5.6,-1.27; 10 -5.6,-2.54; 11 -5.6,-3.81; 19 5.6,-3.81; 20 5.6,-2.54; 21 5.6,-1.27; 22 5.6,0; 23 5.6,1.27; 24 5.6,2.54; 25 5.6,3.81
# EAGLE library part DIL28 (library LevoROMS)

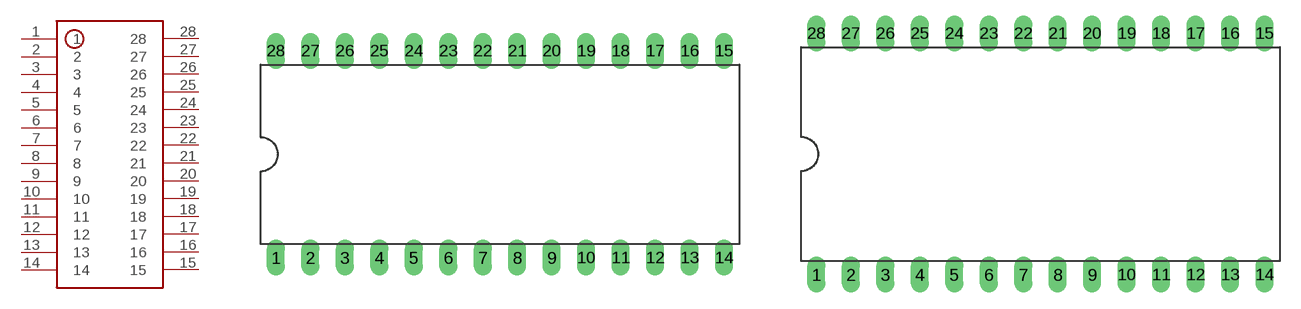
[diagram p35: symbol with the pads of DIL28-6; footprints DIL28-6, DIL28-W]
Designator prefix U

## DIL28A  [DIL28-6]
1  1
2  2
3  3
4  4
5  5
6  6
7  7
8  8
9  9
10  10
11  11
12  12
13  13
14  14
15  15
16  16
17  17
18  18
19  19
20  20
21  21
22  22
23  23
24  24
25  25
26  26
27  27
28  28

## DIL28  [DIL28-W]
Pads as for DIL28-6

## Footprint DIL28-6 (pad centres in mm)
Dual In Line Package 0.6 inch
drill 0.813 long: 1 -16.51,-7.62; 2 -13.97,-7.62; 3 -11.43,-7.62; 4 -8.89,-7.62; 5 -6.35,-7.62; 6 -3.81,-7.62; 7 -1.27,-7.62; 8 1.27,-7.62; 9 3.81,-7.62; 10 6.35,-7.62; 11 8.89,-7.62; 12 11.43,-7.62; 13 13.97,-7.62; 14 16.51,-7.62; 15 16.51,7.62; 16 13.97,7.62; 17 11.43,7.62; 18 8.89,7.62; 19 6.35,7.62; 20 3.81,7.62; 21 1.27,7.62; 22 -1.27,7.62; 23 -3.81,7.62; 24 -6.35,7.62; 25 -8.89,7.62; 26 -11.43,7.62; 27 -13.97,7.62; 28 -16.51,7.62

## Footprint DIL28-W (pad centres in mm)
drill 0.813 long: 1 -16.51,-7.62; 2 -13.97,-7.62; 3 -11.43,-7.62; 4 -8.89,-7.62; 5 -6.35,-7.62; 6 -3.81,-7.62; 7 -1.27,-7.62; 8 1.27,-7.62; 9 3.81,-7.62; 10 6.35,-7.62; 11 8.89,-7.62; 12 11.43,-7.62; 13 13.97,-7.62; 14 16.51,-7.62; 15 16.51,10.16; 16 13.97,10.16; 17 11.43,10.16; 18 8.89,10.16; 19 6.35,10.16; 20 3.81,10.16; 21 1.27,10.16; 22 -1.27,10.16; 23 -3.81,10.16; 24 -6.35,10.16; 25 -8.89,10.16; 26 -11.43,10.16; 27 -13.97,10.16; 28 -16.51,10.16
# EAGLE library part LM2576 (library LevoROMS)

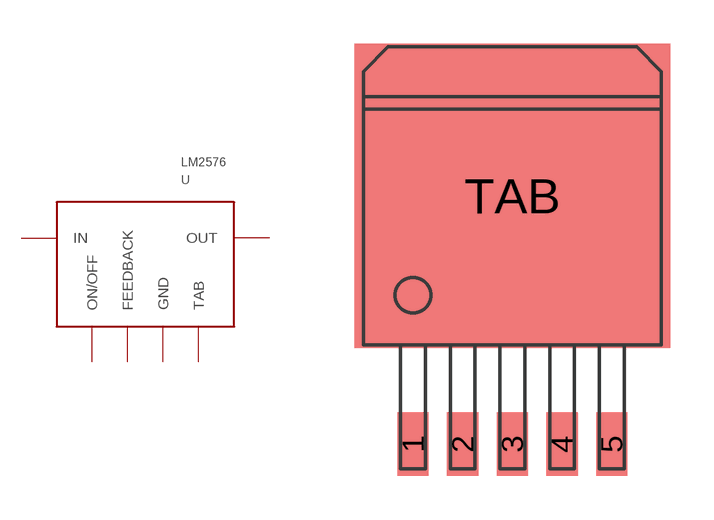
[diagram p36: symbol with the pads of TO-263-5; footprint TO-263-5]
Designator prefix U

## LM2576  [TO-263-5]
1  IN  pwr
2  OUT  pwr
3  GND  pwr
4  FEEDBACK  in
5  ON/OFF  in
TAB  TAB  pwr

## Footprint TO-263-5 (pad centres in mm)
smd 1.07 x 2.16: 1 -3.4,-8.5; 2 -1.7,-8.5; 3 0,-8.5; 4 1.7,-8.5; 5 3.4,-8.5
smd 10.8 x 10.41: TAB 0,0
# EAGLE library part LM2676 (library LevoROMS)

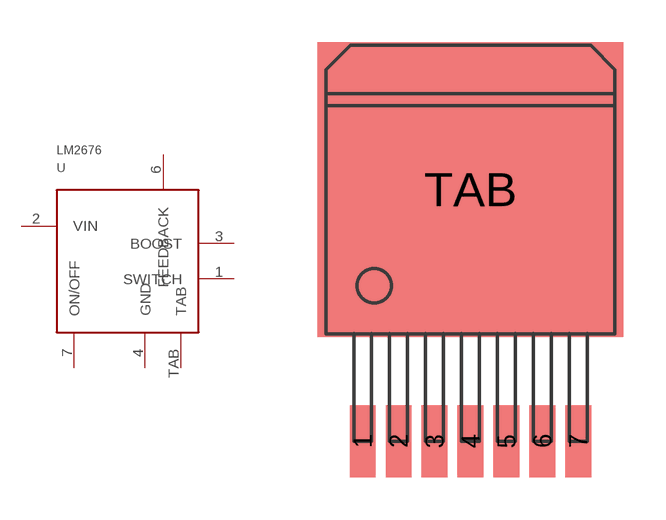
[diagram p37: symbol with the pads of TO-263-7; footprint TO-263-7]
Designator prefix U

## LM2676S  [TO-263-7]
1  SWITCH  pwr
2  VIN  pwr
3  BOOST  pwr
4  GND  pwr
6  FEEDBACK  in
7  ON/OFF  in
TAB  TAB  pwr

## Footprint TO-263-7 (pad centres in mm)
smd 0.914 x 2.54: 1 -3.81,-6.35; 2 -2.54,-6.35; 3 -1.27,-6.35; 4 0,-6.35; 5 1.27,-6.35; 6 2.54,-6.35; 7 3.81,-6.35
smd 10.8 x 10.41: TAB 0,2.54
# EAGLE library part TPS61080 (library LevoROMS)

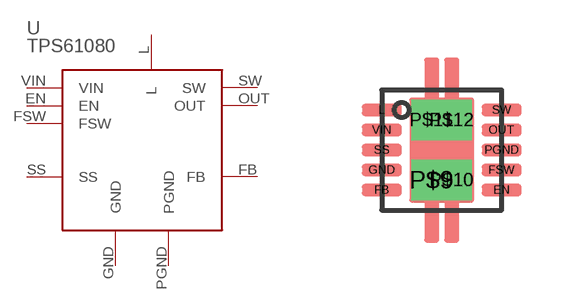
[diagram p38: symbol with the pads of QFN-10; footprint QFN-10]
Designator prefix -

## TPS61080  [QFN-10]
EN  EN  in
FB  FB  in
FSW  FSW  in
GND  GND  pwr
L  L
OUT  OUT  out
PGND  PGND  pwr
SS  SS  in
SW  SW
VIN  VIN  pwr

## Footprint QFN-10 (pad centres in mm)
smd 1 x 0.3: EN 1.75,-0.75; FB -1.25,-0.75; FSW 1.75,-0.25; GND -1.25,-0.25; L -1.25,1.25; OUT 1.75,0.75; PGND 1.75,0.25; SS -1.25,0.25; SW 1.75,1.25; VIN -1.25,0.75
drill 0.5 pad 0.254 square: P$9 0,-0.5; P$10 0.5,-0.5; P$11 0,1; P$12 0.5,1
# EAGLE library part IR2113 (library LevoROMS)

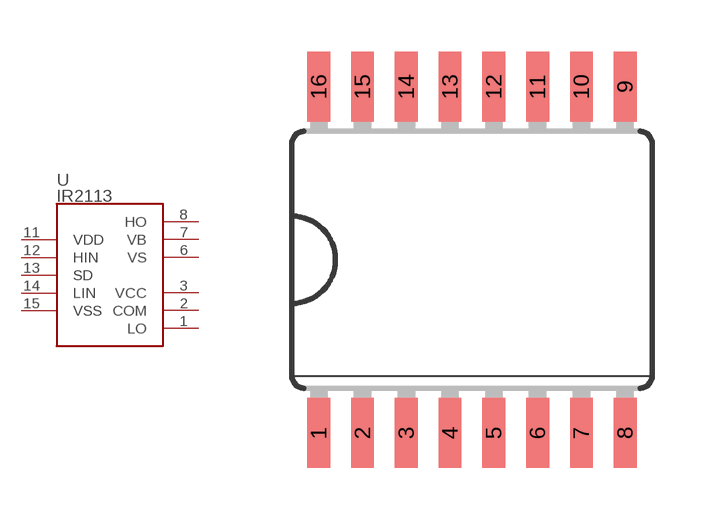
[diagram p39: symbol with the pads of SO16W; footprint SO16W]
Designator prefix -

## IR2113S  [SO16W]
1  LO
2  COM
3  VCC
6  VS
7  VB
8  HO
11  VDD
12  HIN
13  SD
14  LIN
15  VSS

## Footprint SO16W (pad centres in mm)
smd 0.66 x 2.032: 1 -5.715,-5.029; 2 -4.445,-5.029; 3 -3.175,-5.029; 4 -1.905,-5.029; 5 -0.635,-5.029; 6 0.635,-5.029; 7 1.905,-5.029; 8 3.175,-5.029; 9 3.175,5.029; 10 1.905,5.029; 11 0.635,5.029; 12 -0.635,5.029; 13 -1.905,5.029; 14 -3.175,5.029; 15 -4.445,5.029; 16 -5.715,5.029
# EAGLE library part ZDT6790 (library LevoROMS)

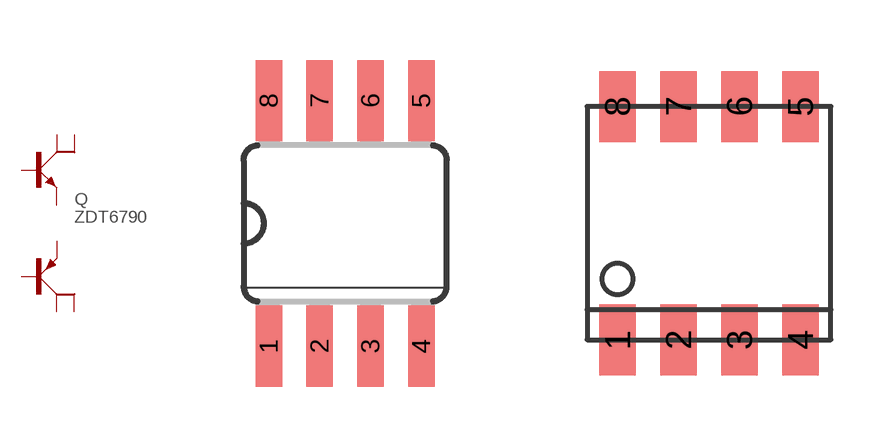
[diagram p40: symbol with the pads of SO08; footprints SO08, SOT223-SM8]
Designator prefix Q

## ZDT6790A  [SO08]
1  E2  pas
2  B2  pas
3  E1  pas
4  B1  pas
5  C1A  pas
6  C1B  pas
7  C2A  pas
8  C2B  pas

## ZDT6790  [SOT223-SM8]
Pads as for SO08

## Footprint SO08 (pad centres in mm)
Small Outline package 150 mil
smd 0.66 x 2.032: 1 -1.905,-3.073; 2 -0.635,-3.073; 3 0.635,-3.073; 4 1.905,-3.073; 5 1.905,3.073; 6 0.635,3.073; 7 -0.635,3.073; 8 -1.905,3.073

## Footprint SOT223-SM8 (pad centres in mm)
smd 0.914 x 1.778: 1 -1.524,-1.524; 2 0,-1.524; 3 1.524,-1.524; 4 3.048,-1.524; 5 3.048,4.318; 6 1.524,4.318; 7 0,4.318; 8 -1.524,4.318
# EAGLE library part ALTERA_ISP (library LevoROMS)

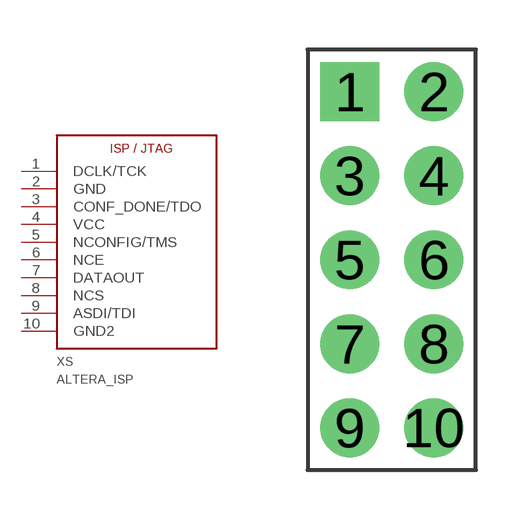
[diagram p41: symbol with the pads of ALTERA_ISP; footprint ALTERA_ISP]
Designator prefix XS

## ALTERA_ISP  [ALTERA_ISP]
1  DCLK/TCK
2  GND  pwr
3  CONF_DONE/TDO
4  VCC  pwr
5  NCONFIG/TMS
6  NCE
7  DATAOUT
8  NCS
9  ASDI/TDI
10  GND2  pwr

## Footprint ALTERA_ISP (pad centres in mm)
drill 0.8 pad 1.778 square: 1 -1.27,2.54
drill 0.8 pad 1.778 round: 2 1.27,2.54; 3 -1.27,0; 4 1.27,0; 5 -1.27,-2.54; 6 1.27,-2.54; 7 -1.27,-5.08; 8 1.27,-5.08; 9 -1.27,-7.62; 10 1.27,-7.62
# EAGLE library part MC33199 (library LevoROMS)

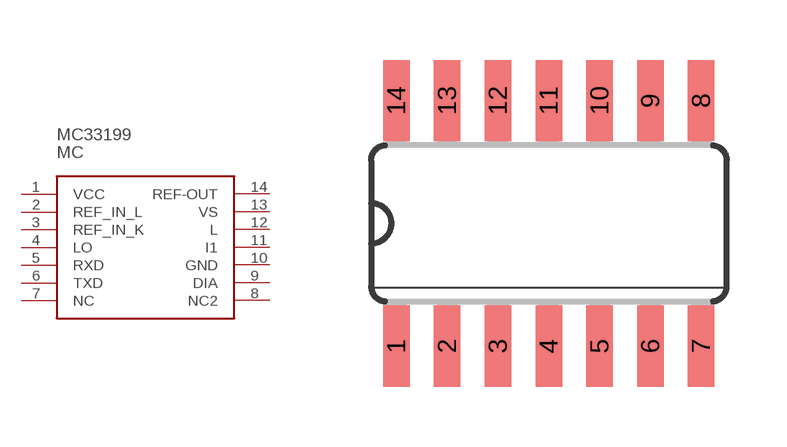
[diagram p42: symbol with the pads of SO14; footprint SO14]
Designator prefix MC

## MC33199  [SO14]
1  VCC
2  REF_IN_L
3  REF_IN_K
4  LO
5  RXD
6  TXD
7  NC
8  NC2
9  DIA
10  GND
11  I1
12  L
13  VS
14  REF-OUT

## Footprint SO14 (pad centres in mm)
Small Outline package 150 mil
smd 0.66 x 2.032: 1 -3.81,-3.073; 2 -2.54,-3.073; 3 -1.27,-3.073; 4 0,-3.073; 5 1.27,-3.073; 6 2.54,-3.073; 7 3.81,-3.073; 8 3.81,3.073; 9 2.54,3.073; 10 1.27,3.073; 11 0,3.073; 12 -1.27,3.073; 13 -2.54,3.073; 14 -3.81,3.073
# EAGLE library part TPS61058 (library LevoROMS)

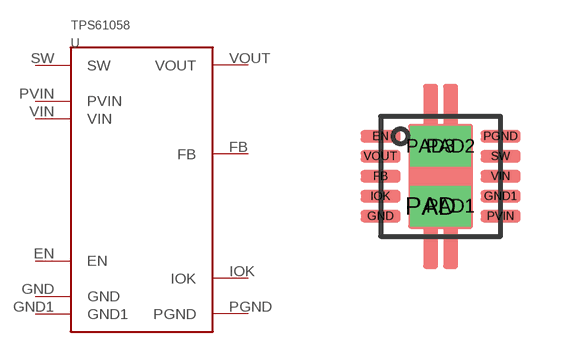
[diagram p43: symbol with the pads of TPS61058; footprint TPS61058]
Designator prefix U

## TPS61058  [TPS61058]
EN  EN
FB  FB
GND  GND
GND1  GND1
IOK  IOK
PGND  PGND
PVIN  PVIN
SW  SW
VIN  VIN
VOUT  VOUT

## Footprint TPS61058 (pad centres in mm)
smd 1 x 0.3: EN -1.25,1.25; FB -1.25,0.25; GND -1.25,-0.75; GND1 1.75,-0.25; IOK -1.25,-0.25; PGND 1.75,1.25; PVIN 1.75,-0.75; SW 1.75,0.75; VIN 1.75,0.25; VOUT -1.25,0.75
drill 0.5 pad 0.254 square: PAD 0,-0.5; PAD1 0.5,-0.5; PAD2 0.5,1; PAD3 0,1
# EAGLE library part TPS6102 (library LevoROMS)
TPS61020, TPS61024, TPS61025, TPS61026, TPS61027, TPS61028, TPS61029 96% EFFICIENT SYNCHRONOUS BOOST CONVERTER

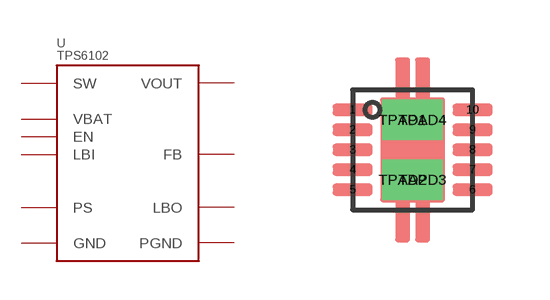
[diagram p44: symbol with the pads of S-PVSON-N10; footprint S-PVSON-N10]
Designator prefix U

## TPS61020  [S-PVSON-N10]
1  EN
2  VOUT
3  FB
4  LBO
5  GND
6  VBAT
7  LBI
8  PS
9  SW
10  PGND

## Footprint S-PVSON-N10 (pad centres in mm)
smd 1 x 0.3: 1 -1.25,1.25; 2 -1.25,0.75; 3 -1.25,0.25; 4 -1.25,-0.25; 5 -1.25,-0.75; 6 1.75,-0.75; 7 1.75,-0.25; 8 1.75,0.25; 9 1.75,0.75; 10 1.75,1.25
drill 0.5 pad 0.254 square: TAPD3 0.5,-0.5; TPAD1 0,1; TPAD2 0,-0.5; TPAD4 0.5,1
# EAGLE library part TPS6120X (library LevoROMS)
TPS61200, TPS61201, TPS61202 LOW INPUT VOLTAGE SYNCHRONOUS BOOST CONVERTER WITH 1.3-A SWITCHES

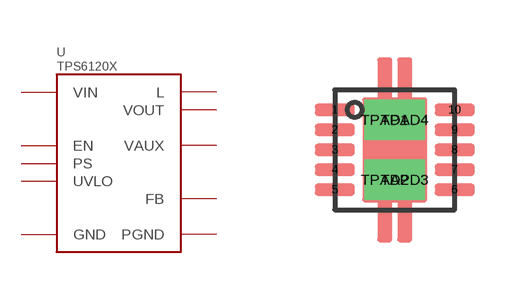
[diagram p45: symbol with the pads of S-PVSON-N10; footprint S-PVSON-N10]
Designator prefix -

## TPS6120X  [S-PVSON-N10]
1  VAUX
2  VOUT
3  L
4  PGND
5  VIN
6  EN
7  UVLO
8  PS
9  GND
10  FB

## Footprint S-PVSON-N10 (pad centres in mm)
smd 1 x 0.3: 1 -1.25,1.25; 2 -1.25,0.75; 3 -1.25,0.25; 4 -1.25,-0.25; 5 -1.25,-0.75; 6 1.75,-0.75; 7 1.75,-0.25; 8 1.75,0.25; 9 1.75,0.75; 10 1.75,1.25
drill 0.5 pad 0.254 square: TAPD3 0.5,-0.5; TPAD1 0,1; TPAD2 0,-0.5; TPAD4 0.5,1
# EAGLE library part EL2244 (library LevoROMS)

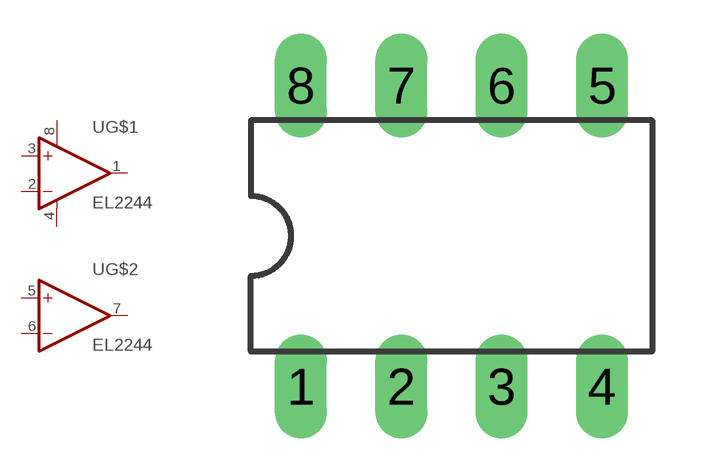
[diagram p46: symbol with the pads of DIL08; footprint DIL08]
Designator prefix U; gates G$1=OPAMP+- G$2=OPAMP

## EL2244  [DIL08]
1  G$1:OUT  out
2  G$1:-IN  in
3  G$1:+IN  in
4  G$1:V-  pwr
5  G$2:+IN  in
6  G$2:-IN  in
7  G$2:OUT  out
8  G$1:V+  pwr

## Footprint DIL08 (pad centres in mm)
Dual In Line Package
drill 0.813 long: 1 -3.81,-3.81; 2 -1.27,-3.81; 3 1.27,-3.81; 4 3.81,-3.81; 5 3.81,3.81; 6 1.27,3.81; 7 -1.27,3.81; 8 -3.81,3.81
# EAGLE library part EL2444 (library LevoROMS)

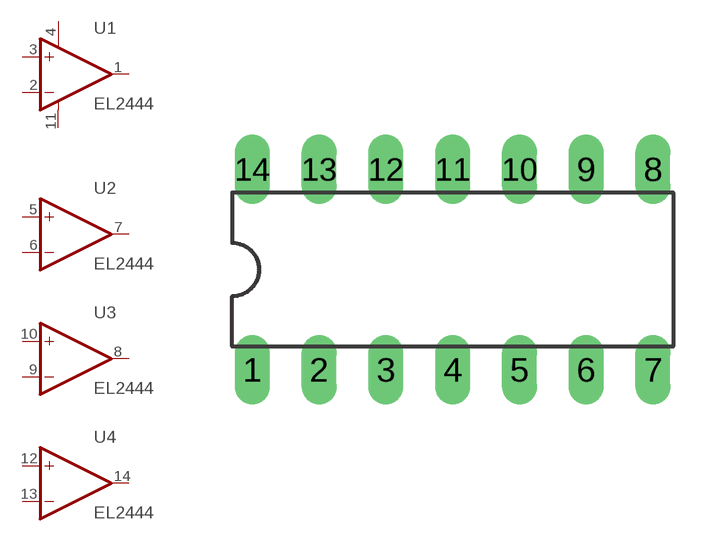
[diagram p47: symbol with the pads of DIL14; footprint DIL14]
Designator prefix U; gates 1=OPAMP+- 2=OPAMP 3=OPAMP 4=OPAMP

## EL2444  [DIL14]
1  1:OUT  out
2  1:-IN  in
3  1:+IN  in
4  1:V+  pwr
5  2:+IN  in
6  2:-IN  in
7  2:OUT  out
8  3:OUT  out
9  3:-IN  in
10  3:+IN  in
11  1:V-  pwr
12  4:+IN  in
13  4:-IN  in
14  4:OUT  out

## Footprint DIL14 (pad centres in mm)
Dual In Line Package
drill 0.813 long: 1 -7.62,-3.81; 2 -5.08,-3.81; 3 -2.54,-3.81; 4 0,-3.81; 5 2.54,-3.81; 6 5.08,-3.81; 7 7.62,-3.81; 8 7.62,3.81; 9 5.08,3.81; 10 2.54,3.81; 11 0,3.81; 12 -2.54,3.81; 13 -5.08,3.81; 14 -7.62,3.81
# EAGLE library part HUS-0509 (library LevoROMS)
DC/DC converter for BNC LAN. Typical Vin=5V, Vout=9V 200mA, unregulated. (Group Tek HUS-0509B, KUS-05090, FUS-05090)

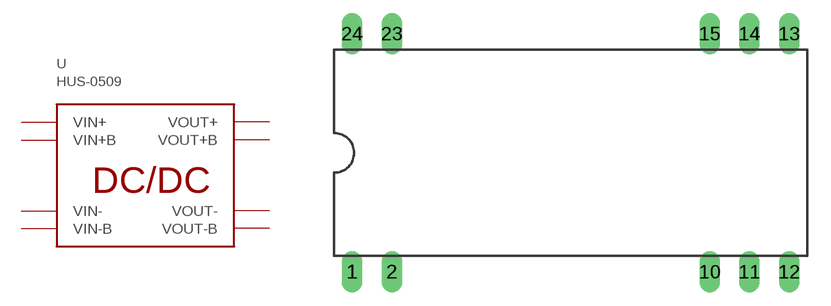
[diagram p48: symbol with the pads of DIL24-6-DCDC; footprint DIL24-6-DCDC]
Designator prefix U

## HUS-0509  [DIL24-6-DCDC]
1  VIN+  pwr
10  VOUT-  pwr
11  VOUT+  pwr
12  VIN-  pwr
13  VIN-B  pwr
14  VOUT+B  pwr
15  VOUT-B  pwr
24  VIN+B  pwr

## Footprint DIL24-6-DCDC (pad centres in mm)
drill 0.813 long: 1 -13.97,-7.62; 2 -11.43,-7.62; 10 8.89,-7.62; 11 11.43,-7.62; 12 13.97,-7.62; 13 13.97,7.62; 14 11.43,7.62; 15 8.89,7.62; 23 -11.43,7.62; 24 -13.97,7.62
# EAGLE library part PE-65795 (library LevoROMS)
ISDN S-interface transformer. SMD. 2000Vrms. PE-65792, PE-65793, PE-65795, PE-65798, PE-65799.

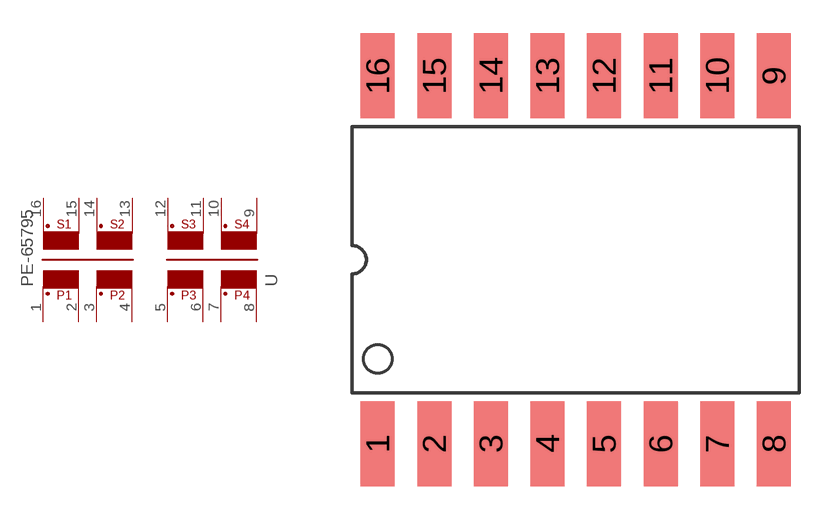
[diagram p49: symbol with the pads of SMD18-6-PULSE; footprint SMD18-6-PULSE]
Designator prefix -

## PE-65795  [SMD18-6-PULSE]
1  1  pas
2  2  pas
3  3  pas
4  4  pas
5  5  pas
6  6  pas
7  7  pas
8  8  pas
9  9  pas
10  10  pas
11  11  pas
12  12  pas
13  13  pas
14  14  pas
15  15  pas
16  16  pas

## Footprint SMD18-6-PULSE (pad centres in mm)
smd 1.524 x 3.81: 1 -13.97,-7.62; 2 -11.43,-7.62; 3 -8.89,-7.62; 4 -6.35,-7.62; 5 -3.81,-7.62; 6 -1.27,-7.62; 7 1.27,-7.62; 8 3.81,-7.62; 9 3.81,8.89; 10 1.27,8.89; 11 -1.27,8.89; 12 -3.81,8.89; 13 -6.35,8.89; 14 -8.89,8.89; 15 -11.43,8.89; 16 -13.97,8.89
